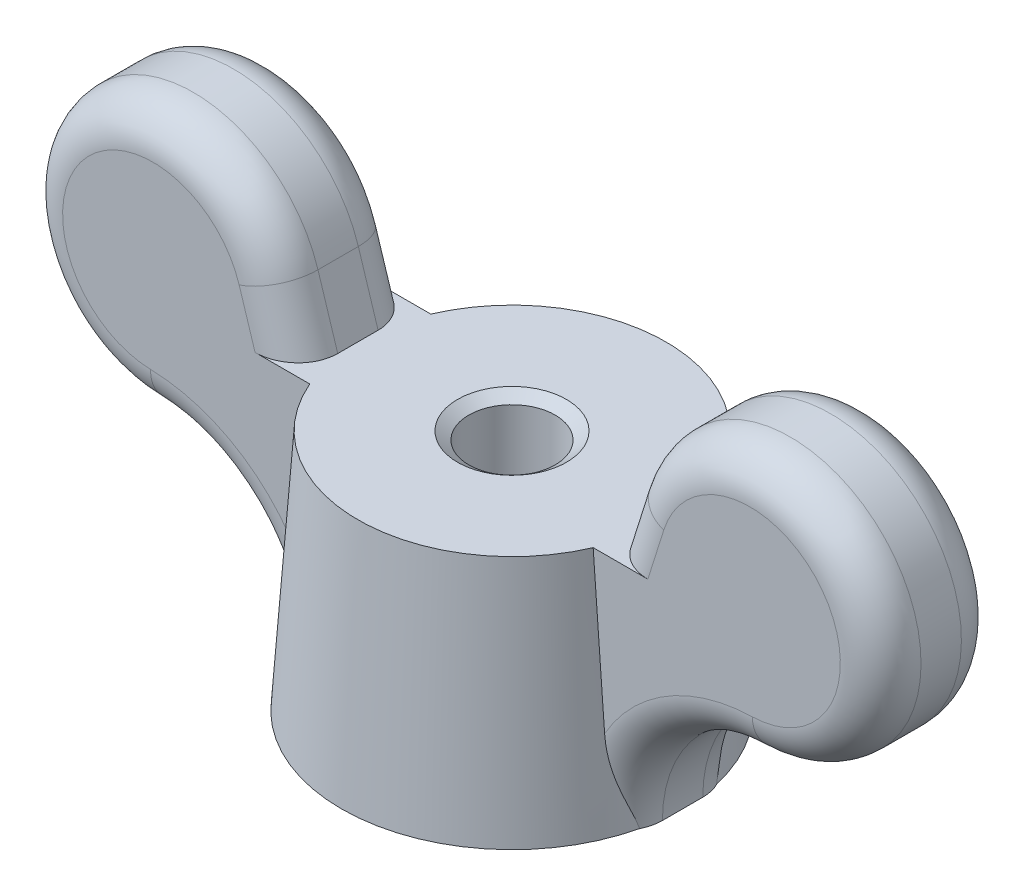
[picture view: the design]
ISO-10303-21;
HEADER;
FILE_DESCRIPTION(('STEP AP214'),'2;1');
FILE_NAME('part.step','',(''),(''),'','','');
FILE_SCHEMA(('AUTOMOTIVE_DESIGN { 1 0 10303 214 1 1 1 1 }'));
ENDSEC;
DATA;
#1=APPLICATION_CONTEXT('core data for automotive mechanical design processes');
#2=APPLICATION_PROTOCOL_DEFINITION('international standard','automotive_design',2000,#1);
#3=PRODUCT_CONTEXT('',#1,'mechanical');
#4=PRODUCT('Part','Part','',(#3));
#5=PRODUCT_RELATED_PRODUCT_CATEGORY('part','',(#4));
#6=PRODUCT_DEFINITION_FORMATION('','',#4);
#7=PRODUCT_DEFINITION_CONTEXT('part definition',#1,'design');
#8=PRODUCT_DEFINITION('design','',#6,#7);
#9=PRODUCT_DEFINITION_SHAPE('','',#8);
#10=(LENGTH_UNIT() NAMED_UNIT(*) SI_UNIT(.MILLI.,.METRE.));
#11=(NAMED_UNIT(*) PLANE_ANGLE_UNIT() SI_UNIT($,.RADIAN.));
#12=(NAMED_UNIT(*) SI_UNIT($,.STERADIAN.) SOLID_ANGLE_UNIT());
#13=UNCERTAINTY_MEASURE_WITH_UNIT(LENGTH_MEASURE(1.E-05),#10,'distance_accuracy_value','');
#14=(GEOMETRIC_REPRESENTATION_CONTEXT(3) GLOBAL_UNCERTAINTY_ASSIGNED_CONTEXT((#13)) GLOBAL_UNIT_ASSIGNED_CONTEXT((#10,
#11,#12)) REPRESENTATION_CONTEXT('',''));
#15=CARTESIAN_POINT('',(0.,0.,0.));
#16=DIRECTION('',(0.,0.,1.));
#17=DIRECTION('',(1.,0.,0.));
#18=AXIS2_PLACEMENT_3D('',#15,#16,#17);
#19=CARTESIAN_POINT('',(3.93700000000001,0.,1.397));
#20=DIRECTION('',(0.,1.,0.));
#21=DIRECTION('',(-1.,0.,0.));
#22=AXIS2_PLACEMENT_3D('',#19,#20,#21);
#23=PLANE('',#22);
#24=CARTESIAN_POINT('',(0.,0.,0.));
#25=DIRECTION('',(0.,-1.,0.));
#26=DIRECTION('',(0.,0.,-1.));
#27=AXIS2_PLACEMENT_3D('',#24,#25,#26);
#28=CIRCLE('',#27,3.937);
#29=CARTESIAN_POINT('',(-3.83538975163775,0.,-0.888681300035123));
#30=VERTEX_POINT('',#29);
#31=CARTESIAN_POINT('',(3.83538975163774,0.,-0.88868130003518));
#32=VERTEX_POINT('',#31);
#33=EDGE_CURVE('E212',#30,#32,#28,.T.);
#34=ORIENTED_EDGE('',*,*,#33,.T.);
#35=CARTESIAN_POINT('',(3.00566666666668,0.,-0.465666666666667));
#36=DIRECTION('',(0.,1.,0.));
#37=DIRECTION('',(-1.,0.,0.));
#38=AXIS2_PLACEMENT_3D('',#35,#36,#37);
#39=CIRCLE('',#38,0.931333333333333);
#40=CARTESIAN_POINT('',(3.93700000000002,0.,-0.465666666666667));
#41=VERTEX_POINT('',#40);
#42=EDGE_CURVE('E436',#32,#41,#39,.F.);
#43=ORIENTED_EDGE('',*,*,#42,.T.);
#44=DIRECTION('',(0.,0.,-1.));
#45=VECTOR('',#44,1.);
#46=CARTESIAN_POINT('',(3.93700000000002,0.,1.397));
#47=LINE('',#46,#45);
#48=CARTESIAN_POINT('',(3.93700000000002,0.,0.465666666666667));
#49=VERTEX_POINT('',#48);
#50=EDGE_CURVE('E475',#49,#41,#47,.T.);
#51=ORIENTED_EDGE('',*,*,#50,.F.);
#52=CARTESIAN_POINT('',(3.00566666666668,0.,0.465666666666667));
#53=DIRECTION('',(0.,1.,0.));
#54=DIRECTION('',(-1.,0.,0.));
#55=AXIS2_PLACEMENT_3D('',#52,#53,#54);
#56=CIRCLE('',#55,0.931333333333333);
#57=CARTESIAN_POINT('',(3.83538975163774,0.,0.88868130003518));
#58=VERTEX_POINT('',#57);
#59=EDGE_CURVE('E441',#49,#58,#56,.F.);
#60=ORIENTED_EDGE('',*,*,#59,.T.);
#61=CARTESIAN_POINT('',(-3.83538975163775,0.,0.888681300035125));
#62=VERTEX_POINT('',#61);
#63=EDGE_CURVE('E199',#58,#62,#28,.T.);
#64=ORIENTED_EDGE('',*,*,#63,.T.);
#65=CARTESIAN_POINT('',(-3.00566666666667,0.,0.465666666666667));
#66=DIRECTION('',(0.,1.,0.));
#67=DIRECTION('',(-1.,0.,0.));
#68=AXIS2_PLACEMENT_3D('',#65,#66,#67);
#69=CIRCLE('',#68,0.931333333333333);
#70=CARTESIAN_POINT('',(-3.937,0.,0.465666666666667));
#71=VERTEX_POINT('',#70);
#72=EDGE_CURVE('E444',#62,#71,#69,.F.);
#73=ORIENTED_EDGE('',*,*,#72,.T.);
#74=DIRECTION('',(0.,0.,-1.));
#75=VECTOR('',#74,1.);
#76=CARTESIAN_POINT('',(-3.937,0.,1.397));
#77=LINE('',#76,#75);
#78=CARTESIAN_POINT('',(-3.937,0.,-0.465666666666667));
#79=VERTEX_POINT('',#78);
#80=EDGE_CURVE('E470',#71,#79,#77,.T.);
#81=ORIENTED_EDGE('',*,*,#80,.T.);
#82=CARTESIAN_POINT('',(-3.00566666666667,0.,-0.465666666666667));
#83=DIRECTION('',(0.,1.,0.));
#84=DIRECTION('',(-1.,0.,0.));
#85=AXIS2_PLACEMENT_3D('',#82,#83,#84);
#86=CIRCLE('',#85,0.931333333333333);
#87=EDGE_CURVE('E438',#79,#30,#86,.F.);
#88=ORIENTED_EDGE('',*,*,#87,.T.);
#89=EDGE_LOOP('',(#34,#43,#51,#60,#64,#73,#81,#88));
#90=FACE_BOUND('',#89,.T.);
#91=CARTESIAN_POINT('',(0.,0.,0.));
#92=DIRECTION('',(0.,1.,0.));
#93=DIRECTION('',(-1.,0.,0.));
#94=AXIS2_PLACEMENT_3D('',#91,#92,#93);
#95=CIRCLE('',#94,1.25729999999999);
#96=CARTESIAN_POINT('',(-1.25729999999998,0.,0.));
#97=VERTEX_POINT('',#96);
#98=EDGE_CURVE('E500',#97,#97,#95,.T.);
#99=ORIENTED_EDGE('',*,*,#98,.T.);
#100=EDGE_LOOP('',(#99));
#101=FACE_BOUND('',#100,.T.);
#102=ADVANCED_FACE('F47',(#90,#101),#23,.F.);
#103=CARTESIAN_POINT('',(6.88920679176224,6.12720679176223,1.397));
#104=DIRECTION('',(0.,0.,-1.));
#105=DIRECTION('',(-1.,0.,0.));
#106=AXIS2_PLACEMENT_3D('',#103,#104,#105);
#107=PLANE('',#106);
#108=CARTESIAN_POINT('',(-6.88920679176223,6.12720679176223,1.397));
#109=DIRECTION('',(0.,0.,-1.));
#110=DIRECTION('',(-1.,0.,0.));
#111=AXIS2_PLACEMENT_3D('',#108,#109,#110);
#112=CIRCLE('',#111,2.08545987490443);
#113=CARTESIAN_POINT('',(-4.90026835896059,6.75431667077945,1.397));
#114=VERTEX_POINT('',#113);
#115=CARTESIAN_POINT('',(-6.9437490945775,4.04246027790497,1.397));
#116=VERTEX_POINT('',#115);
#117=EDGE_CURVE('E398',#114,#116,#112,.F.);
#118=ORIENTED_EDGE('',*,*,#117,.T.);
#119=CARTESIAN_POINT('',(-7.04951019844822,0.,1.397));
#120=DIRECTION('',(0.,0.,-1.));
#121=DIRECTION('',(-1.,0.,0.));
#122=AXIS2_PLACEMENT_3D('',#119,#120,#121);
#123=CIRCLE('',#122,4.04384353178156);
#124=CARTESIAN_POINT('',(-3.53461000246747,1.9995367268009,1.397));
#125=VERTEX_POINT('',#124);
#126=EDGE_CURVE('E409',#116,#125,#123,.T.);
#127=ORIENTED_EDGE('',*,*,#126,.T.);
#128=CARTESIAN_POINT('',(-2.53867458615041,15.2435415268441,1.397));
#129=CARTESIAN_POINT('',(-2.60883110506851,14.3418946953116,1.397));
#130=CARTESIAN_POINT('',(-2.67834194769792,13.4401979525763,1.397));
#131=CARTESIAN_POINT('',(-2.81629610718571,11.6367239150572,1.397));
#132=CARTESIAN_POINT('',(-2.88473942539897,10.7349466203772,1.397));
#133=CARTESIAN_POINT('',(-3.0752390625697,8.20936047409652,1.397));
#134=CARTESIAN_POINT('',(-3.19634976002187,6.58548035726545,1.397));
#135=CARTESIAN_POINT('',(-3.43663846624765,3.33757667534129,1.397));
#136=CARTESIAN_POINT('',(-3.55581647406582,1.71355311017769,1.397));
#137=CARTESIAN_POINT('',(-3.79275127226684,-1.53460548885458,1.397));
#138=CARTESIAN_POINT('',(-3.91050805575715,-3.15874052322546,1.397));
#139=CARTESIAN_POINT('',(-4.14491971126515,-6.40708829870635,1.397));
#140=CARTESIAN_POINT('',(-4.26157458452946,-8.03130103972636,1.397));
#141=CARTESIAN_POINT('',(-4.37783858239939,-9.65554152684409,1.397));
#142=B_SPLINE_CURVE_WITH_KNOTS('',3,(#128,#129,#130,#131,#132,#133,#134,#135,#136,#137,#138,
#139,#140,#141),.UNSPECIFIED.,.F.,.F.,(4,2,2,2,2,2,4),(0.,2.71311566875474,5.42622789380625,
10.3113965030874,15.1965675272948,20.0817622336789,24.9669514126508),.UNSPECIFIED.);
#143=CARTESIAN_POINT('',(-3.27009587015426,5.588,1.397));
#144=VERTEX_POINT('',#143);
#145=EDGE_CURVE('E198',#144,#125,#142,.T.);
#146=ORIENTED_EDGE('',*,*,#145,.F.);
#147=DIRECTION('',(-1.,0.,0.));
#148=VECTOR('',#147,1.);
#149=CARTESIAN_POINT('',(-3.55599999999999,5.588,1.397));
#150=LINE('',#149,#148);
#151=CARTESIAN_POINT('',(-4.53253012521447,5.588,1.397));
#152=VERTEX_POINT('',#151);
#153=EDGE_CURVE('E208',#144,#152,#150,.T.);
#154=ORIENTED_EDGE('',*,*,#153,.T.);
#155=DIRECTION('',(-0.300705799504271,0.953716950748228,0.));
#156=VECTOR('',#155,1.);
#157=CARTESIAN_POINT('',(-3.65436939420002,2.80282998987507,1.397));
#158=LINE('',#157,#156);
#159=EDGE_CURVE('E401',#152,#114,#158,.T.);
#160=ORIENTED_EDGE('',*,*,#159,.T.);
#161=EDGE_LOOP('',(#118,#127,#146,#154,#160));
#162=FACE_BOUND('',#161,.T.);
#163=ADVANCED_FACE('F232',(#162),#107,.F.);
#164=CARTESIAN_POINT('',(4.37783858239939,-9.65554152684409,1.397));
#165=CARTESIAN_POINT('',(4.27544426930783,-8.2249837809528,1.397));
#166=CARTESIAN_POINT('',(4.17273962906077,-6.79444812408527,1.397));
#167=CARTESIAN_POINT('',(3.96650348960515,-3.93343820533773,1.397));
#168=CARTESIAN_POINT('',(3.86297199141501,-2.50296394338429,1.397));
#169=CARTESIAN_POINT('',(3.66000814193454,0.287349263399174,1.397));
#170=CARTESIAN_POINT('',(3.56062550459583,1.64719182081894,1.397));
#171=CARTESIAN_POINT('',(3.36066061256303,4.36678847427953,1.397));
#172=CARTESIAN_POINT('',(3.26007835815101,5.72654257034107,1.397));
#173=CARTESIAN_POINT('',(3.05734265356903,8.44593710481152,1.397));
#174=CARTESIAN_POINT('',(2.95518919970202,9.80557754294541,1.397));
#175=CARTESIAN_POINT('',(2.80035690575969,11.8449172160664,1.397));
#176=CARTESIAN_POINT('',(2.74847909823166,12.524677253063,1.397));
#177=CARTESIAN_POINT('',(2.64408340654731,13.8841483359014,1.397));
#178=CARTESIAN_POINT('',(2.59156552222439,14.5638593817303,1.397));
#179=CARTESIAN_POINT('',(2.53867458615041,15.2435415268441,1.397));
#180=B_SPLINE_CURVE_WITH_KNOTS('',3,(#164,#165,#166,#167,#168,#169,#170,#171,#172,#173,#174,
#175,#176,#177,#178,#179),.UNSPECIFIED.,.F.,.F.,(4,2,2,2,2,2,2,4),(0.,4.30265288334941,
8.60530046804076,12.6957081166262,16.786114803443,20.8765311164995,22.9217411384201,
24.9669516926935),.UNSPECIFIED.);
#181=CARTESIAN_POINT('',(3.53461000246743,1.99953672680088,1.397));
#182=VERTEX_POINT('',#181);
#183=CARTESIAN_POINT('',(3.27009587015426,5.588,1.397));
#184=VERTEX_POINT('',#183);
#185=EDGE_CURVE('E187',#182,#184,#180,.T.);
#186=ORIENTED_EDGE('',*,*,#185,.F.);
#187=CARTESIAN_POINT('',(7.04951019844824,0.,1.397));
#188=DIRECTION('',(0.,0.,-1.));
#189=DIRECTION('',(-1.,0.,0.));
#190=AXIS2_PLACEMENT_3D('',#187,#188,#189);
#191=CIRCLE('',#190,4.04384353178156);
#192=CARTESIAN_POINT('',(6.94374909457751,4.04246027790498,1.397));
#193=VERTEX_POINT('',#192);
#194=EDGE_CURVE('E414',#182,#193,#191,.T.);
#195=ORIENTED_EDGE('',*,*,#194,.T.);
#196=CARTESIAN_POINT('',(6.88920679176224,6.12720679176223,1.397));
#197=DIRECTION('',(0.,0.,-1.));
#198=DIRECTION('',(-1.,0.,0.));
#199=AXIS2_PLACEMENT_3D('',#196,#197,#198);
#200=CIRCLE('',#199,2.08545987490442);
#201=CARTESIAN_POINT('',(4.90026835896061,6.75431667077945,1.397));
#202=VERTEX_POINT('',#201);
#203=EDGE_CURVE('E416',#193,#202,#200,.F.);
#204=ORIENTED_EDGE('',*,*,#203,.T.);
#205=DIRECTION('',(-0.300705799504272,-0.953716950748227,0.));
#206=VECTOR('',#205,1.);
#207=CARTESIAN_POINT('',(4.90026835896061,6.75431667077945,1.397));
#208=LINE('',#207,#206);
#209=CARTESIAN_POINT('',(4.53253012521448,5.588,1.397));
#210=VERTEX_POINT('',#209);
#211=EDGE_CURVE('E205',#202,#210,#208,.T.);
#212=ORIENTED_EDGE('',*,*,#211,.T.);
#213=EDGE_CURVE('E202',#210,#184,#150,.T.);
#214=ORIENTED_EDGE('',*,*,#213,.T.);
#215=EDGE_LOOP('',(#186,#195,#204,#212,#214));
#216=FACE_BOUND('',#215,.T.);
#217=ADVANCED_FACE('F203',(#216),#107,.F.);
#218=CARTESIAN_POINT('',(6.88920679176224,6.12720679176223,-1.397));
#219=DIRECTION('',(0.,0.,-1.));
#220=DIRECTION('',(-1.,0.,0.));
#221=AXIS2_PLACEMENT_3D('',#218,#219,#220);
#222=PLANE('',#221);
#223=CARTESIAN_POINT('',(-2.53867458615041,15.2435415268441,-1.397));
#224=CARTESIAN_POINT('',(-2.60883110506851,14.3418946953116,-1.397));
#225=CARTESIAN_POINT('',(-2.67834194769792,13.4401979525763,-1.397));
#226=CARTESIAN_POINT('',(-2.81629610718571,11.6367239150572,-1.397));
#227=CARTESIAN_POINT('',(-2.88473942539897,10.7349466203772,-1.397));
#228=CARTESIAN_POINT('',(-3.0752390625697,8.20936047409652,-1.397));
#229=CARTESIAN_POINT('',(-3.19634976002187,6.58548035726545,-1.397));
#230=CARTESIAN_POINT('',(-3.43663846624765,3.33757667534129,-1.397));
#231=CARTESIAN_POINT('',(-3.55581647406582,1.71355311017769,-1.397));
#232=CARTESIAN_POINT('',(-3.79275127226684,-1.53460548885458,-1.397));
#233=CARTESIAN_POINT('',(-3.91050805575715,-3.15874052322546,-1.397));
#234=CARTESIAN_POINT('',(-4.14491971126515,-6.40708829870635,-1.397));
#235=CARTESIAN_POINT('',(-4.26157458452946,-8.03130103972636,-1.397));
#236=CARTESIAN_POINT('',(-4.37783858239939,-9.65554152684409,-1.397));
#237=B_SPLINE_CURVE_WITH_KNOTS('',3,(#223,#224,#225,#226,#227,#228,#229,#230,#231,#232,#233,
#234,#235,#236),.UNSPECIFIED.,.F.,.F.,(4,2,2,2,2,2,4),(0.,2.71311566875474,5.42622789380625,
10.3113965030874,15.1965675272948,20.0817622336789,24.9669514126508),.UNSPECIFIED.);
#238=CARTESIAN_POINT('',(-3.27009587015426,5.588,-1.397));
#239=VERTEX_POINT('',#238);
#240=CARTESIAN_POINT('',(-3.53461000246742,1.9995367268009,-1.397));
#241=VERTEX_POINT('',#240);
#242=EDGE_CURVE('E255',#239,#241,#237,.T.);
#243=ORIENTED_EDGE('',*,*,#242,.T.);
#244=CARTESIAN_POINT('',(-7.04951019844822,0.,-1.397));
#245=DIRECTION('',(0.,0.,-1.));
#246=DIRECTION('',(-1.,0.,0.));
#247=AXIS2_PLACEMENT_3D('',#244,#245,#246);
#248=CIRCLE('',#247,4.04384353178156);
#249=CARTESIAN_POINT('',(-6.9437490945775,4.04246027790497,-1.397));
#250=VERTEX_POINT('',#249);
#251=EDGE_CURVE('E421',#241,#250,#248,.F.);
#252=ORIENTED_EDGE('',*,*,#251,.T.);
#253=CARTESIAN_POINT('',(-6.88920679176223,6.12720679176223,-1.397));
#254=DIRECTION('',(0.,0.,-1.));
#255=DIRECTION('',(-1.,0.,0.));
#256=AXIS2_PLACEMENT_3D('',#253,#254,#255);
#257=CIRCLE('',#256,2.08545987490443);
#258=CARTESIAN_POINT('',(-4.90026835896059,6.75431667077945,-1.397));
#259=VERTEX_POINT('',#258);
#260=EDGE_CURVE('E372',#250,#259,#257,.T.);
#261=ORIENTED_EDGE('',*,*,#260,.T.);
#262=DIRECTION('',(-0.300705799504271,0.953716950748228,0.));
#263=VECTOR('',#262,1.);
#264=CARTESIAN_POINT('',(-4.44422838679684,5.30794266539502,-1.397));
#265=LINE('',#264,#263);
#266=CARTESIAN_POINT('',(-4.53253012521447,5.588,-1.397));
#267=VERTEX_POINT('',#266);
#268=EDGE_CURVE('E424',#259,#267,#265,.F.);
#269=ORIENTED_EDGE('',*,*,#268,.T.);
#270=DIRECTION('',(-1.,0.,0.));
#271=VECTOR('',#270,1.);
#272=CARTESIAN_POINT('',(-3.55599999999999,5.588,-1.397));
#273=LINE('',#272,#271);
#274=EDGE_CURVE('E489',#239,#267,#273,.T.);
#275=ORIENTED_EDGE('',*,*,#274,.F.);
#276=EDGE_LOOP('',(#243,#252,#261,#269,#275));
#277=FACE_BOUND('',#276,.T.);
#278=ADVANCED_FACE('F526',(#277),#222,.T.);
#279=CARTESIAN_POINT('',(6.88920679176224,6.12720679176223,-1.397));
#280=DIRECTION('',(0.,0.,-1.));
#281=DIRECTION('',(-1.,0.,0.));
#282=AXIS2_PLACEMENT_3D('',#279,#280,#281);
#283=CIRCLE('',#282,2.08545987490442);
#284=CARTESIAN_POINT('',(4.90026835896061,6.75431667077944,-1.397));
#285=VERTEX_POINT('',#284);
#286=CARTESIAN_POINT('',(6.94374909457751,4.04246027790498,-1.397));
#287=VERTEX_POINT('',#286);
#288=EDGE_CURVE('E448',#285,#287,#283,.T.);
#289=ORIENTED_EDGE('',*,*,#288,.T.);
#290=CARTESIAN_POINT('',(7.04951019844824,0.,-1.397));
#291=DIRECTION('',(0.,0.,-1.));
#292=DIRECTION('',(-1.,0.,0.));
#293=AXIS2_PLACEMENT_3D('',#290,#291,#292);
#294=CIRCLE('',#293,4.04384353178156);
#295=CARTESIAN_POINT('',(3.53461000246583,1.99953672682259,-1.397));
#296=VERTEX_POINT('',#295);
#297=EDGE_CURVE('E446',#287,#296,#294,.F.);
#298=ORIENTED_EDGE('',*,*,#297,.T.);
#299=CARTESIAN_POINT('',(4.37783858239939,-9.65554152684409,-1.397));
#300=CARTESIAN_POINT('',(4.27544426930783,-8.2249837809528,-1.397));
#301=CARTESIAN_POINT('',(4.17273962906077,-6.79444812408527,-1.397));
#302=CARTESIAN_POINT('',(3.96650348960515,-3.93343820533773,-1.397));
#303=CARTESIAN_POINT('',(3.86297199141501,-2.50296394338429,-1.397));
#304=CARTESIAN_POINT('',(3.66000814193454,0.287349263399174,-1.397));
#305=CARTESIAN_POINT('',(3.56062550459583,1.64719182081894,-1.397));
#306=CARTESIAN_POINT('',(3.36066061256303,4.36678847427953,-1.397));
#307=CARTESIAN_POINT('',(3.26007835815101,5.72654257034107,-1.397));
#308=CARTESIAN_POINT('',(3.05734265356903,8.44593710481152,-1.397));
#309=CARTESIAN_POINT('',(2.95518919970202,9.80557754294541,-1.397));
#310=CARTESIAN_POINT('',(2.80035690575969,11.8449172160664,-1.397));
#311=CARTESIAN_POINT('',(2.74847909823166,12.524677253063,-1.397));
#312=CARTESIAN_POINT('',(2.64408340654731,13.8841483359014,-1.397));
#313=CARTESIAN_POINT('',(2.59156552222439,14.5638593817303,-1.397));
#314=CARTESIAN_POINT('',(2.53867458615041,15.2435415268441,-1.397));
#315=B_SPLINE_CURVE_WITH_KNOTS('',3,(#299,#300,#301,#302,#303,#304,#305,#306,#307,#308,#309,
#310,#311,#312,#313,#314),.UNSPECIFIED.,.F.,.F.,(4,2,2,2,2,2,2,4),(0.,4.30265288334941,
8.60530046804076,12.6957081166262,16.786114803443,20.8765311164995,22.9217411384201,
24.9669516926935),.UNSPECIFIED.);
#316=CARTESIAN_POINT('',(3.27009587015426,5.588,-1.397));
#317=VERTEX_POINT('',#316);
#318=EDGE_CURVE('E245',#296,#317,#315,.T.);
#319=ORIENTED_EDGE('',*,*,#318,.T.);
#320=CARTESIAN_POINT('',(4.53253012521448,5.588,-1.397));
#321=VERTEX_POINT('',#320);
#322=EDGE_CURVE('E487',#321,#317,#273,.T.);
#323=ORIENTED_EDGE('',*,*,#322,.F.);
#324=DIRECTION('',(-0.300705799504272,-0.953716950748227,0.));
#325=VECTOR('',#324,1.);
#326=CARTESIAN_POINT('',(4.90026835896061,6.75431667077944,-1.397));
#327=LINE('',#326,#325);
#328=EDGE_CURVE('E450',#321,#285,#327,.F.);
#329=ORIENTED_EDGE('',*,*,#328,.T.);
#330=EDGE_LOOP('',(#289,#298,#319,#323,#329));
#331=FACE_BOUND('',#330,.T.);
#332=ADVANCED_FACE('F343',(#331),#222,.T.);
#333=CARTESIAN_POINT('',(-4.01203997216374,7.03437400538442,1.397));
#334=DIRECTION('',(-0.953716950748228,-0.300705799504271,0.));
#335=DIRECTION('',(0.300705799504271,-0.953716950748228,0.));
#336=AXIS2_PLACEMENT_3D('',#333,#334,#335);
#337=PLANE('',#336);
#338=DIRECTION('',(0.,0.,-1.));
#339=VECTOR('',#338,1.);
#340=CARTESIAN_POINT('',(-3.55599999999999,5.588,1.397));
#341=LINE('',#340,#339);
#342=CARTESIAN_POINT('',(-3.55599999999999,5.588,0.465666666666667));
#343=VERTEX_POINT('',#342);
#344=CARTESIAN_POINT('',(-3.55599999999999,5.588,-0.465666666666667));
#345=VERTEX_POINT('',#344);
#346=EDGE_CURVE('E207',#343,#345,#341,.T.);
#347=ORIENTED_EDGE('',*,*,#346,.T.);
#348=DIRECTION('',(-0.300705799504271,0.953716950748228,0.));
#349=VECTOR('',#348,1.);
#350=CARTESIAN_POINT('',(-4.01203997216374,7.03437400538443,-0.465666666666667));
#351=LINE('',#350,#349);
#352=CARTESIAN_POINT('',(-4.01203997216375,7.03437400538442,-0.465666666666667));
#353=VERTEX_POINT('',#352);
#354=EDGE_CURVE('E402',#345,#353,#351,.T.);
#355=ORIENTED_EDGE('',*,*,#354,.T.);
#356=DIRECTION('',(0.,0.,-1.));
#357=VECTOR('',#356,1.);
#358=CARTESIAN_POINT('',(-4.01203997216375,7.03437400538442,1.397));
#359=LINE('',#358,#357);
#360=CARTESIAN_POINT('',(-4.01203997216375,7.03437400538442,0.465666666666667));
#361=VERTEX_POINT('',#360);
#362=EDGE_CURVE('E464',#361,#353,#359,.T.);
#363=ORIENTED_EDGE('',*,*,#362,.F.);
#364=DIRECTION('',(-0.300705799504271,0.953716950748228,0.));
#365=VECTOR('',#364,1.);
#366=CARTESIAN_POINT('',(-4.01203997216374,7.03437400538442,0.465666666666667));
#367=LINE('',#366,#365);
#368=EDGE_CURVE('E71',#361,#343,#367,.F.);
#369=ORIENTED_EDGE('',*,*,#368,.T.);
#370=EDGE_LOOP('',(#347,#355,#363,#369));
#371=FACE_BOUND('',#370,.T.);
#372=ADVANCED_FACE('F340',(#371),#337,.F.);
#373=CARTESIAN_POINT('',(-6.88920679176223,6.12720679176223,1.397));
#374=DIRECTION('',(0.,0.,-1.));
#375=DIRECTION('',(-1.,0.,0.));
#376=AXIS2_PLACEMENT_3D('',#373,#374,#375);
#377=CYLINDRICAL_SURFACE('',#376,3.01679320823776);
#378=ORIENTED_EDGE('',*,*,#362,.T.);
#379=CARTESIAN_POINT('',(-6.88920679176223,6.12720679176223,-0.465666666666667));
#380=DIRECTION('',(0.,0.,-1.));
#381=DIRECTION('',(-1.,0.,0.));
#382=AXIS2_PLACEMENT_3D('',#379,#380,#381);
#383=CIRCLE('',#382,3.01679320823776);
#384=CARTESIAN_POINT('',(-6.96810682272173,3.11144552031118,-0.465666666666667));
#385=VERTEX_POINT('',#384);
#386=EDGE_CURVE('E374',#353,#385,#383,.F.);
#387=ORIENTED_EDGE('',*,*,#386,.T.);
#388=DIRECTION('',(0.,0.,-1.));
#389=VECTOR('',#388,1.);
#390=CARTESIAN_POINT('',(-6.96810682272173,3.11144552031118,1.397));
#391=LINE('',#390,#389);
#392=CARTESIAN_POINT('',(-6.96810682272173,3.11144552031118,0.465666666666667));
#393=VERTEX_POINT('',#392);
#394=EDGE_CURVE('E468',#393,#385,#391,.T.);
#395=ORIENTED_EDGE('',*,*,#394,.F.);
#396=CARTESIAN_POINT('',(-6.88920679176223,6.12720679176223,0.465666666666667));
#397=DIRECTION('',(0.,0.,-1.));
#398=DIRECTION('',(-1.,0.,0.));
#399=AXIS2_PLACEMENT_3D('',#396,#397,#398);
#400=CIRCLE('',#399,3.01679320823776);
#401=EDGE_CURVE('E397',#393,#361,#400,.T.);
#402=ORIENTED_EDGE('',*,*,#401,.T.);
#403=EDGE_LOOP('',(#378,#387,#395,#402));
#404=FACE_BOUND('',#403,.T.);
#405=ADVANCED_FACE('F336',(#404),#377,.T.);
#406=CARTESIAN_POINT('',(-7.04951019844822,0.,1.397));
#407=DIRECTION('',(0.,0.,-1.));
#408=DIRECTION('',(-1.,0.,0.));
#409=AXIS2_PLACEMENT_3D('',#406,#407,#408);
#410=CYLINDRICAL_SURFACE('',#409,3.11251019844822);
#411=ORIENTED_EDGE('',*,*,#394,.T.);
#412=CARTESIAN_POINT('',(-7.04951019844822,0.,-0.465666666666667));
#413=DIRECTION('',(0.,0.,-1.));
#414=DIRECTION('',(-1.,0.,0.));
#415=AXIS2_PLACEMENT_3D('',#412,#413,#414);
#416=CIRCLE('',#415,3.11251019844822);
#417=EDGE_CURVE('E427',#385,#79,#416,.T.);
#418=ORIENTED_EDGE('',*,*,#417,.T.);
#419=ORIENTED_EDGE('',*,*,#80,.F.);
#420=CARTESIAN_POINT('',(-7.04951019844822,0.,0.465666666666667));
#421=DIRECTION('',(0.,0.,-1.));
#422=DIRECTION('',(-1.,0.,0.));
#423=AXIS2_PLACEMENT_3D('',#420,#421,#422);
#424=CIRCLE('',#423,3.11251019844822);
#425=EDGE_CURVE('E430',#71,#393,#424,.F.);
#426=ORIENTED_EDGE('',*,*,#425,.T.);
#427=EDGE_LOOP('',(#411,#418,#419,#426));
#428=FACE_BOUND('',#427,.T.);
#429=ADVANCED_FACE('F333',(#428),#410,.F.);
#430=CARTESIAN_POINT('',(7.04951019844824,0.,1.397));
#431=DIRECTION('',(0.,0.,-1.));
#432=DIRECTION('',(-1.,0.,0.));
#433=AXIS2_PLACEMENT_3D('',#430,#431,#432);
#434=CYLINDRICAL_SURFACE('',#433,3.11251019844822);
#435=ORIENTED_EDGE('',*,*,#50,.T.);
#436=CARTESIAN_POINT('',(7.04951019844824,0.,-0.465666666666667));
#437=DIRECTION('',(0.,0.,-1.));
#438=DIRECTION('',(-1.,0.,0.));
#439=AXIS2_PLACEMENT_3D('',#436,#437,#438);
#440=CIRCLE('',#439,3.11251019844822);
#441=CARTESIAN_POINT('',(6.96810682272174,3.11144552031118,-0.465666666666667));
#442=VERTEX_POINT('',#441);
#443=EDGE_CURVE('E452',#41,#442,#440,.T.);
#444=ORIENTED_EDGE('',*,*,#443,.T.);
#445=DIRECTION('',(0.,0.,-1.));
#446=VECTOR('',#445,1.);
#447=CARTESIAN_POINT('',(6.96810682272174,3.11144552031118,1.397));
#448=LINE('',#447,#446);
#449=CARTESIAN_POINT('',(6.96810682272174,3.11144552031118,0.465666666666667));
#450=VERTEX_POINT('',#449);
#451=EDGE_CURVE('E477',#450,#442,#448,.T.);
#452=ORIENTED_EDGE('',*,*,#451,.F.);
#453=CARTESIAN_POINT('',(7.04951019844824,0.,0.465666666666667));
#454=DIRECTION('',(0.,0.,-1.));
#455=DIRECTION('',(-1.,0.,0.));
#456=AXIS2_PLACEMENT_3D('',#453,#454,#455);
#457=CIRCLE('',#456,3.11251019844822);
#458=EDGE_CURVE('E454',#450,#49,#457,.F.);
#459=ORIENTED_EDGE('',*,*,#458,.T.);
#460=EDGE_LOOP('',(#435,#444,#452,#459));
#461=FACE_BOUND('',#460,.T.);
#462=ADVANCED_FACE('F331',(#461),#434,.F.);
#463=CARTESIAN_POINT('',(6.88920679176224,6.12720679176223,1.397));
#464=DIRECTION('',(0.,0.,-1.));
#465=DIRECTION('',(-1.,0.,0.));
#466=AXIS2_PLACEMENT_3D('',#463,#464,#465);
#467=CYLINDRICAL_SURFACE('',#466,3.01679320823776);
#468=ORIENTED_EDGE('',*,*,#451,.T.);
#469=CARTESIAN_POINT('',(6.88920679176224,6.12720679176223,-0.465666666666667));
#470=DIRECTION('',(0.,0.,-1.));
#471=DIRECTION('',(-1.,0.,0.));
#472=AXIS2_PLACEMENT_3D('',#469,#470,#471);
#473=CIRCLE('',#472,3.01679320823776);
#474=CARTESIAN_POINT('',(4.01203997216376,7.03437400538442,-0.465666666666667));
#475=VERTEX_POINT('',#474);
#476=EDGE_CURVE('E432',#442,#475,#473,.F.);
#477=ORIENTED_EDGE('',*,*,#476,.T.);
#478=DIRECTION('',(0.,0.,-1.));
#479=VECTOR('',#478,1.);
#480=CARTESIAN_POINT('',(4.01203997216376,7.03437400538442,1.397));
#481=LINE('',#480,#479);
#482=CARTESIAN_POINT('',(4.01203997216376,7.03437400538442,0.465666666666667));
#483=VERTEX_POINT('',#482);
#484=EDGE_CURVE('E480',#483,#475,#481,.T.);
#485=ORIENTED_EDGE('',*,*,#484,.F.);
#486=CARTESIAN_POINT('',(6.88920679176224,6.12720679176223,0.465666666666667));
#487=DIRECTION('',(0.,0.,-1.));
#488=DIRECTION('',(-1.,0.,0.));
#489=AXIS2_PLACEMENT_3D('',#486,#487,#488);
#490=CIRCLE('',#489,3.01679320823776);
#491=EDGE_CURVE('E434',#483,#450,#490,.T.);
#492=ORIENTED_EDGE('',*,*,#491,.T.);
#493=EDGE_LOOP('',(#468,#477,#485,#492));
#494=FACE_BOUND('',#493,.T.);
#495=ADVANCED_FACE('F523',(#494),#467,.T.);
#496=CARTESIAN_POINT('',(3.55600000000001,5.588,1.397));
#497=DIRECTION('',(0.953716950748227,-0.300705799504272,0.));
#498=DIRECTION('',(0.300705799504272,0.953716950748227,0.));
#499=AXIS2_PLACEMENT_3D('',#496,#497,#498);
#500=PLANE('',#499);
#501=ORIENTED_EDGE('',*,*,#484,.T.);
#502=DIRECTION('',(-0.300705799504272,-0.953716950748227,0.));
#503=VECTOR('',#502,1.);
#504=CARTESIAN_POINT('',(3.55600000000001,5.588,-0.465666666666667));
#505=LINE('',#504,#503);
#506=CARTESIAN_POINT('',(3.55600000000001,5.588,-0.465666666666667));
#507=VERTEX_POINT('',#506);
#508=EDGE_CURVE('E403',#475,#507,#505,.T.);
#509=ORIENTED_EDGE('',*,*,#508,.T.);
#510=DIRECTION('',(0.,0.,-1.));
#511=VECTOR('',#510,1.);
#512=CARTESIAN_POINT('',(3.55600000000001,5.588,1.397));
#513=LINE('',#512,#511);
#514=CARTESIAN_POINT('',(3.55600000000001,5.588,0.465666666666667));
#515=VERTEX_POINT('',#514);
#516=EDGE_CURVE('E483',#515,#507,#513,.T.);
#517=ORIENTED_EDGE('',*,*,#516,.F.);
#518=DIRECTION('',(-0.300705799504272,-0.953716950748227,0.));
#519=VECTOR('',#518,1.);
#520=CARTESIAN_POINT('',(3.55600000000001,5.588,0.465666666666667));
#521=LINE('',#520,#519);
#522=EDGE_CURVE('E405',#515,#483,#521,.F.);
#523=ORIENTED_EDGE('',*,*,#522,.T.);
#524=EDGE_LOOP('',(#501,#509,#517,#523));
#525=FACE_BOUND('',#524,.T.);
#526=ADVANCED_FACE('F518',(#525),#500,.F.);
#527=CARTESIAN_POINT('',(-3.55599999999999,5.588,1.397));
#528=DIRECTION('',(0.,-1.,0.));
#529=DIRECTION('',(1.,0.,0.));
#530=AXIS2_PLACEMENT_3D('',#527,#528,#529);
#531=PLANE('',#530);
#532=CARTESIAN_POINT('',(0.,5.588,0.));
#533=DIRECTION('',(0.,1.,0.));
#534=DIRECTION('',(-1.,0.,0.));
#535=AXIS2_PLACEMENT_3D('',#532,#533,#534);
#536=CIRCLE('',#535,1.25729999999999);
#537=CARTESIAN_POINT('',(-1.25729999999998,5.588,0.));
#538=VERTEX_POINT('',#537);
#539=EDGE_CURVE('E507',#538,#538,#536,.T.);
#540=ORIENTED_EDGE('',*,*,#539,.F.);
#541=EDGE_LOOP('',(#540));
#542=FACE_BOUND('',#541,.T.);
#543=ORIENTED_EDGE('',*,*,#213,.F.);
#544=CARTESIAN_POINT('',(4.53253012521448,5.588,0.465666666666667));
#545=DIRECTION('',(0.,-1.,0.));
#546=DIRECTION('',(-1.,0.,0.));
#547=AXIS2_PLACEMENT_3D('',#544,#545,#546);
#548=ELLIPSE('',#547,0.976530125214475,0.931333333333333);
#549=EDGE_CURVE('E56',#210,#515,#548,.T.);
#550=ORIENTED_EDGE('',*,*,#549,.T.);
#551=ORIENTED_EDGE('',*,*,#516,.T.);
#552=CARTESIAN_POINT('',(4.53253012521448,5.588,-0.465666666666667));
#553=DIRECTION('',(0.,-1.,0.));
#554=DIRECTION('',(1.,0.,0.));
#555=AXIS2_PLACEMENT_3D('',#552,#553,#554);
#556=ELLIPSE('',#555,0.976530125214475,0.931333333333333);
#557=EDGE_CURVE('E494',#507,#321,#556,.T.);
#558=ORIENTED_EDGE('',*,*,#557,.T.);
#559=ORIENTED_EDGE('',*,*,#322,.T.);
#560=CARTESIAN_POINT('',(0.,5.588,0.));
#561=DIRECTION('',(0.,-1.,0.));
#562=DIRECTION('',(0.,0.,-1.));
#563=AXIS2_PLACEMENT_3D('',#560,#561,#562);
#564=CIRCLE('',#563,3.55599999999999);
#565=EDGE_CURVE('E213',#239,#317,#564,.T.);
#566=ORIENTED_EDGE('',*,*,#565,.F.);
#567=ORIENTED_EDGE('',*,*,#274,.T.);
#568=CARTESIAN_POINT('',(-4.53253012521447,5.588,-0.465666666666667));
#569=DIRECTION('',(0.,-1.,0.));
#570=DIRECTION('',(1.,0.,0.));
#571=AXIS2_PLACEMENT_3D('',#568,#569,#570);
#572=ELLIPSE('',#571,0.976530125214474,0.931333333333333);
#573=EDGE_CURVE('E64',#267,#345,#572,.T.);
#574=ORIENTED_EDGE('',*,*,#573,.T.);
#575=ORIENTED_EDGE('',*,*,#346,.F.);
#576=CARTESIAN_POINT('',(-4.53253012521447,5.588,0.465666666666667));
#577=DIRECTION('',(0.,-1.,0.));
#578=DIRECTION('',(-1.,0.,0.));
#579=AXIS2_PLACEMENT_3D('',#576,#577,#578);
#580=ELLIPSE('',#579,0.976530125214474,0.931333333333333);
#581=EDGE_CURVE('E11',#343,#152,#580,.T.);
#582=ORIENTED_EDGE('',*,*,#581,.T.);
#583=ORIENTED_EDGE('',*,*,#153,.F.);
#584=EDGE_CURVE('E192',#184,#144,#564,.T.);
#585=ORIENTED_EDGE('',*,*,#584,.F.);
#586=EDGE_LOOP('',(#543,#550,#551,#558,#559,#566,#567,#574,#575,#582,#583,#585));
#587=FACE_BOUND('',#586,.T.);
#588=ADVANCED_FACE('F211',(#542,#587),#531,.F.);
#589=CARTESIAN_POINT('',(0.,5.588,0.));
#590=DIRECTION('',(0.,-1.,0.));
#591=DIRECTION('',(0.,0.,-1.));
#592=AXIS2_PLACEMENT_3D('',#589,#590,#591);
#593=CONICAL_SURFACE('',#592,3.55599999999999,0.0680764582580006);
#594=ORIENTED_EDGE('',*,*,#242,.F.);
#595=ORIENTED_EDGE('',*,*,#565,.T.);
#596=ORIENTED_EDGE('',*,*,#318,.F.);
#597=CARTESIAN_POINT('',(3.53461000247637,1.9995367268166,-1.397));
#598=CARTESIAN_POINT('',(3.5403856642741,1.92056024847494,-1.3970008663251));
#599=CARTESIAN_POINT('',(3.54741439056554,1.84172264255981,-1.39387313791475));
#600=CARTESIAN_POINT('',(3.5636036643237,1.68474687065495,-1.38185084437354));
#601=CARTESIAN_POINT('',(3.57276300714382,1.60660833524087,-1.3729595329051));
#602=CARTESIAN_POINT('',(3.59275731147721,1.45205231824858,-1.3500017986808));
#603=CARTESIAN_POINT('',(3.60357665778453,1.37562571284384,-1.33598207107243));
#604=CARTESIAN_POINT('',(3.62651629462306,1.22400343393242,-1.30328976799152));
#605=CARTESIAN_POINT('',(3.63863629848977,1.1488074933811,-1.28461821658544));
#606=CARTESIAN_POINT('',(3.66646560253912,0.983393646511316,-1.23869667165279));
#607=CARTESIAN_POINT('',(3.68238034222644,0.8934854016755,-1.21046366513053));
#608=CARTESIAN_POINT('',(3.70654378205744,0.759831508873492,-1.16471089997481));
#609=CARTESIAN_POINT('',(3.71465054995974,0.715461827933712,-1.14888483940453));
#610=CARTESIAN_POINT('',(3.73084654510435,0.627034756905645,-1.11636399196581));
#611=CARTESIAN_POINT('',(3.73893577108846,0.582977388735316,-1.0996691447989));
#612=CARTESIAN_POINT('',(3.75506834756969,0.494532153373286,-1.06556161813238));
#613=CARTESIAN_POINT('',(3.76311008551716,0.450146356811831,-1.04814286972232));
#614=CARTESIAN_POINT('',(3.77890797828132,0.361339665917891,-1.01330955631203));
#615=CARTESIAN_POINT('',(3.78666422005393,0.316918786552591,-0.995894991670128));
#616=CARTESIAN_POINT('',(3.80170787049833,0.227715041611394,-0.961929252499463));
#617=CARTESIAN_POINT('',(3.80899580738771,0.182932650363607,-0.945377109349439));
#618=CARTESIAN_POINT('',(3.8193814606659,0.115027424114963,-0.922318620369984));
#619=CARTESIAN_POINT('',(3.82275430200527,0.0922554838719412,-0.914923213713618));
#620=CARTESIAN_POINT('',(3.82926378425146,0.0463860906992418,-0.901039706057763));
#621=CARTESIAN_POINT('',(3.83240024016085,0.0232883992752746,-0.894552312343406));
#622=CARTESIAN_POINT('',(3.83538975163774,0.,-0.888681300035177));
#623=B_SPLINE_CURVE_WITH_KNOTS('',3,(#597,#598,#599,#600,#601,#602,#603,#604,#605,#606,#607,
#608,#609,#610,#611,#612,#613,#614,#615,#616,#617,#618,#619,#620,#621,#622),.UNSPECIFIED.,.F.,
.F.,(4,2,2,2,2,2,2,2,2,2,2,2,4),(0.,0.237422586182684,0.474711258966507,0.709891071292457,
0.945019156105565,1.23154825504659,1.37494258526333,1.51834688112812,1.66340969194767,
1.80842794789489,1.95327965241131,2.02579911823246,2.09837476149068),.UNSPECIFIED.);
#624=EDGE_CURVE('E265',#296,#32,#623,.T.);
#625=ORIENTED_EDGE('',*,*,#624,.T.);
#626=ORIENTED_EDGE('',*,*,#33,.F.);
#627=CARTESIAN_POINT('',(-3.83538975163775,0.,-0.888681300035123));
#628=CARTESIAN_POINT('',(-3.83051751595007,0.0378560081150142,-0.898301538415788));
#629=CARTESIAN_POINT('',(-3.82527800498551,0.075207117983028,-0.909424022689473));
#630=CARTESIAN_POINT('',(-3.81425921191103,0.149157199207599,-0.933583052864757));
#631=CARTESIAN_POINT('',(-3.80848067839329,0.185757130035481,-0.946616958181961));
#632=CARTESIAN_POINT('',(-3.79656551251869,0.25855678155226,-0.973537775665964));
#633=CARTESIAN_POINT('',(-3.79042895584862,0.29475658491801,-0.987424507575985));
#634=CARTESIAN_POINT('',(-3.77790312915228,0.367010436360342,-1.01549935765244));
#635=CARTESIAN_POINT('',(-3.7715137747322,0.403064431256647,-1.02968757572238));
#636=CARTESIAN_POINT('',(-3.75195594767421,0.51208173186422,-1.07240529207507));
#637=CARTESIAN_POINT('',(-3.73853910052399,0.585071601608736,-1.10075749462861));
#638=CARTESIAN_POINT('',(-3.71163229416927,0.731908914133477,-1.15508099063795));
#639=CARTESIAN_POINT('',(-3.69814236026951,0.805756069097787,-1.18105305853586));
#640=CARTESIAN_POINT('',(-3.67197525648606,0.952560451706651,-1.22885625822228));
#641=CARTESIAN_POINT('',(-3.6592858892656,1.02548371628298,-1.25078378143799));
#642=CARTESIAN_POINT('',(-3.63477174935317,1.17259949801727,-1.29065637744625));
#643=CARTESIAN_POINT('',(-3.62294731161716,1.24679249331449,-1.30859991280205));
#644=CARTESIAN_POINT('',(-3.60066480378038,1.39593917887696,-1.33983321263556));
#645=CARTESIAN_POINT('',(-3.59019976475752,1.47088667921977,-1.35314735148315));
#646=CARTESIAN_POINT('',(-3.57096365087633,1.62169151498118,-1.37476209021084));
#647=CARTESIAN_POINT('',(-3.56219148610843,1.69754823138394,-1.3830659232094));
#648=CARTESIAN_POINT('',(-3.55253061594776,1.79241931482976,-1.39001772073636));
#649=CARTESIAN_POINT('',(-3.55068490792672,1.81116695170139,-1.39122534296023));
#650=CARTESIAN_POINT('',(-3.54712001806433,1.84870045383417,-1.39330517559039));
#651=CARTESIAN_POINT('',(-3.54540088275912,1.86748633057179,-1.39417726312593));
#652=CARTESIAN_POINT('',(-3.5420890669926,1.90514346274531,-1.39558102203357));
#653=CARTESIAN_POINT('',(-3.5404968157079,1.9240147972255,-1.39611157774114));
#654=CARTESIAN_POINT('',(-3.53744963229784,1.96176786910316,-1.39682098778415));
#655=CARTESIAN_POINT('',(-3.53599464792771,1.98064959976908,-1.39699997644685));
#656=CARTESIAN_POINT('',(-3.53461000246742,1.9995367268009,-1.397));
#657=B_SPLINE_CURVE_WITH_KNOTS('',3,(#627,#628,#629,#630,#631,#632,#633,#634,#635,#636,#637,
#638,#639,#640,#641,#642,#643,#644,#645,#646,#647,#648,#649,#650,#651,#652,#653,#654,#655,#656),
.UNSPECIFIED.,.F.,.F.,(4,2,2,2,2,2,2,2,2,2,2,2,2,2,4),(0.,0.117951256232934,0.235741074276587,
0.353506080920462,0.471310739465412,0.709629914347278,0.947871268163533,1.17937006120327,
1.41095803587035,1.64130751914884,1.8715081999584,1.92813714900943,1.98478681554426,
2.04162060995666,2.09843268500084),.UNSPECIFIED.);
#658=EDGE_CURVE('E273',#30,#241,#657,.T.);
#659=ORIENTED_EDGE('',*,*,#658,.T.);
#660=EDGE_LOOP('',(#594,#595,#596,#625,#626,#659));
#661=FACE_BOUND('',#660,.T.);
#662=ADVANCED_FACE('F235',(#661),#593,.T.);
#663=ORIENTED_EDGE('',*,*,#584,.T.);
#664=ORIENTED_EDGE('',*,*,#145,.T.);
#665=CARTESIAN_POINT('',(-3.53461000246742,1.9995367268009,1.397));
#666=CARTESIAN_POINT('',(-3.54038566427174,1.92056024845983,1.39700086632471));
#667=CARTESIAN_POINT('',(-3.54741439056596,1.84172264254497,1.39387313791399));
#668=CARTESIAN_POINT('',(-3.56360366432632,1.68474687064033,1.38185084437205));
#669=CARTESIAN_POINT('',(-3.57276300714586,1.6066083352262,1.37295953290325));
#670=CARTESIAN_POINT('',(-3.59275731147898,1.45205231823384,1.35000179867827));
#671=CARTESIAN_POINT('',(-3.6035766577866,1.37562571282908,1.33598207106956));
#672=CARTESIAN_POINT('',(-3.62651629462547,1.22400343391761,1.303289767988));
#673=CARTESIAN_POINT('',(-3.63863629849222,1.14880749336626,1.28461821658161));
#674=CARTESIAN_POINT('',(-3.66646560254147,0.983393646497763,1.23869667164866));
#675=CARTESIAN_POINT('',(-3.68238034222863,0.893485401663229,1.21046366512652));
#676=CARTESIAN_POINT('',(-3.70654378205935,0.75983150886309,1.16471089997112));
#677=CARTESIAN_POINT('',(-3.71465054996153,0.715461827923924,1.14888483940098));
#678=CARTESIAN_POINT('',(-3.73084654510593,0.627034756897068,1.11636399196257));
#679=CARTESIAN_POINT('',(-3.73893577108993,0.582977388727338,1.09966914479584));
#680=CARTESIAN_POINT('',(-3.75506834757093,0.494532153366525,1.06556161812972));
#681=CARTESIAN_POINT('',(-3.76311008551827,0.450146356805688,1.04814286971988));
#682=CARTESIAN_POINT('',(-3.77890797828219,0.361339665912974,1.01330955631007));
#683=CARTESIAN_POINT('',(-3.78666422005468,0.316918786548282,0.995894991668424));
#684=CARTESIAN_POINT('',(-3.80170787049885,0.227715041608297,0.961929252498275));
#685=CARTESIAN_POINT('',(-3.80899580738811,0.182932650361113,0.945377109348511));
#686=CARTESIAN_POINT('',(-3.81938146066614,0.115027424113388,0.922318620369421));
#687=CARTESIAN_POINT('',(-3.82275430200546,0.0922554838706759,0.914923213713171));
#688=CARTESIAN_POINT('',(-3.82926378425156,0.0463860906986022,0.901039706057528));
#689=CARTESIAN_POINT('',(-3.8324002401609,0.0232883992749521,0.894552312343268));
#690=CARTESIAN_POINT('',(-3.83538975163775,0.,0.888681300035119));
#691=B_SPLINE_CURVE_WITH_KNOTS('',3,(#665,#666,#667,#668,#669,#670,#671,#672,#673,#674,#675,
#676,#677,#678,#679,#680,#681,#682,#683,#684,#685,#686,#687,#688,#689,#690),.UNSPECIFIED.,.F.,
.F.,(4,2,2,2,2,2,2,2,2,2,2,2,4),(0.,0.237422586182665,0.474711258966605,0.709891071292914,
0.945019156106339,1.23154825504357,1.37494258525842,1.51834688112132,1.66340969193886,
1.80842794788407,1.95327965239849,2.02579911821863,2.09837476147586),.UNSPECIFIED.);
#692=EDGE_CURVE('E285',#125,#62,#691,.T.);
#693=ORIENTED_EDGE('',*,*,#692,.T.);
#694=ORIENTED_EDGE('',*,*,#63,.F.);
#695=CARTESIAN_POINT('',(3.83538975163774,0.,0.88868130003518));
#696=CARTESIAN_POINT('',(3.83051751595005,0.0378560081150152,0.898301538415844));
#697=CARTESIAN_POINT('',(3.8252780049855,0.0752071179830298,0.909424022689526));
#698=CARTESIAN_POINT('',(3.81425921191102,0.149157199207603,0.933583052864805));
#699=CARTESIAN_POINT('',(3.80848067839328,0.185757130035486,0.946616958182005));
#700=CARTESIAN_POINT('',(3.79656551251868,0.258556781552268,0.973537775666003));
#701=CARTESIAN_POINT('',(3.79042895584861,0.294756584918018,0.987424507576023));
#702=CARTESIAN_POINT('',(3.77790312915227,0.367010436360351,1.01549935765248));
#703=CARTESIAN_POINT('',(3.77151377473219,0.403064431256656,1.02968757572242));
#704=CARTESIAN_POINT('',(3.7519559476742,0.51208173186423,1.0724052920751));
#705=CARTESIAN_POINT('',(3.73853910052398,0.585071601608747,1.10075749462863));
#706=CARTESIAN_POINT('',(3.71163229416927,0.731908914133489,1.15508099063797));
#707=CARTESIAN_POINT('',(3.6981423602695,0.8057560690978,1.18105305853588));
#708=CARTESIAN_POINT('',(3.67197525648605,0.952560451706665,1.22885625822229));
#709=CARTESIAN_POINT('',(3.6592858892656,1.02548371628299,1.25078378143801));
#710=CARTESIAN_POINT('',(3.63477174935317,1.17259949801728,1.29065637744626));
#711=CARTESIAN_POINT('',(3.62294731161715,1.24679249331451,1.30859991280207));
#712=CARTESIAN_POINT('',(3.60066480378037,1.39593917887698,1.33983321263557));
#713=CARTESIAN_POINT('',(3.59019976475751,1.47088667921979,1.35314735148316));
#714=CARTESIAN_POINT('',(3.57096365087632,1.6216915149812,1.37476209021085));
#715=CARTESIAN_POINT('',(3.56219148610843,1.69754823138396,1.3830659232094));
#716=CARTESIAN_POINT('',(3.55253061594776,1.79241931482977,1.39001772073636));
#717=CARTESIAN_POINT('',(3.55068490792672,1.8111669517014,1.39122534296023));
#718=CARTESIAN_POINT('',(3.54712001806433,1.84870045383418,1.39330517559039));
#719=CARTESIAN_POINT('',(3.54540088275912,1.86748633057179,1.39417726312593));
#720=CARTESIAN_POINT('',(3.5420890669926,1.90514346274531,1.39558102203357));
#721=CARTESIAN_POINT('',(3.5404968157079,1.92401479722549,1.39611157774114));
#722=CARTESIAN_POINT('',(3.53744963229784,1.96176786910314,1.39682098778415));
#723=CARTESIAN_POINT('',(3.53599464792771,1.98064959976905,1.39699997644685));
#724=CARTESIAN_POINT('',(3.53461000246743,1.99953672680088,1.397));
#725=B_SPLINE_CURVE_WITH_KNOTS('',3,(#695,#696,#697,#698,#699,#700,#701,#702,#703,#704,#705,
#706,#707,#708,#709,#710,#711,#712,#713,#714,#715,#716,#717,#718,#719,#720,#721,#722,#723,#724),
.UNSPECIFIED.,.F.,.F.,(4,2,2,2,2,2,2,2,2,2,2,2,2,2,4),(0.,0.117951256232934,0.235741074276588,
0.353506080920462,0.471310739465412,0.709629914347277,0.947871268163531,1.17937006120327,
1.41095803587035,1.64130751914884,1.8715081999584,1.92813714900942,1.98478681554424,
2.04162060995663,2.0984326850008),.UNSPECIFIED.);
#726=EDGE_CURVE('E194',#58,#182,#725,.T.);
#727=ORIENTED_EDGE('',*,*,#726,.T.);
#728=ORIENTED_EDGE('',*,*,#185,.T.);
#729=EDGE_LOOP('',(#663,#664,#693,#694,#727,#728));
#730=FACE_BOUND('',#729,.T.);
#731=ADVANCED_FACE('F189',(#730),#593,.T.);
#732=CARTESIAN_POINT('',(0.,0.,0.));
#733=DIRECTION('',(0.,-1.,0.));
#734=DIRECTION('',(1.,0.,0.));
#735=AXIS2_PLACEMENT_3D('',#732,#733,#734);
#736=CONICAL_SURFACE('',#735,1.25729999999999,0.959931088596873);
#737=CARTESIAN_POINT('',(0.,0.1822990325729,0.));
#738=DIRECTION('',(0.,1.,0.));
#739=DIRECTION('',(-1.,0.,0.));
#740=AXIS2_PLACEMENT_3D('',#737,#738,#739);
#741=CIRCLE('',#740,0.996949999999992);
#742=CARTESIAN_POINT('',(-0.996949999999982,0.1822990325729,0.));
#743=VERTEX_POINT('',#742);
#744=EDGE_CURVE('E219',#743,#743,#741,.T.);
#745=ORIENTED_EDGE('',*,*,#744,.T.);
#746=EDGE_LOOP('',(#745));
#747=FACE_BOUND('',#746,.T.);
#748=ORIENTED_EDGE('',*,*,#98,.F.);
#749=EDGE_LOOP('',(#748));
#750=FACE_BOUND('',#749,.T.);
#751=ADVANCED_FACE('F576',(#747,#750),#736,.F.);
#752=CARTESIAN_POINT('',(0.,5.4057009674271,0.));
#753=DIRECTION('',(0.,1.,0.));
#754=DIRECTION('',(-1.,0.,0.));
#755=AXIS2_PLACEMENT_3D('',#752,#753,#754);
#756=CONICAL_SURFACE('',#755,0.996949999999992,0.959931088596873);
#757=ORIENTED_EDGE('',*,*,#539,.T.);
#758=EDGE_LOOP('',(#757));
#759=FACE_BOUND('',#758,.T.);
#760=CARTESIAN_POINT('',(0.,5.4057009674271,0.));
#761=DIRECTION('',(0.,1.,0.));
#762=DIRECTION('',(-1.,0.,0.));
#763=AXIS2_PLACEMENT_3D('',#760,#761,#762);
#764=CIRCLE('',#763,0.996949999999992);
#765=CARTESIAN_POINT('',(-0.996949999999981,5.4057009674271,0.));
#766=VERTEX_POINT('',#765);
#767=EDGE_CURVE('E217',#766,#766,#764,.T.);
#768=ORIENTED_EDGE('',*,*,#767,.F.);
#769=EDGE_LOOP('',(#768));
#770=FACE_BOUND('',#769,.T.);
#771=ADVANCED_FACE('F514',(#759,#770),#756,.F.);
#772=CARTESIAN_POINT('',(0.,5.588,0.));
#773=DIRECTION('',(0.,-1.,0.));
#774=DIRECTION('',(0.,0.,-1.));
#775=AXIS2_PLACEMENT_3D('',#772,#773,#774);
#776=CYLINDRICAL_SURFACE('',#775,0.99695);
#777=ORIENTED_EDGE('',*,*,#744,.F.);
#778=EDGE_LOOP('',(#777));
#779=FACE_BOUND('',#778,.T.);
#780=ORIENTED_EDGE('',*,*,#767,.T.);
#781=EDGE_LOOP('',(#780));
#782=FACE_BOUND('',#781,.T.);
#783=ADVANCED_FACE('F240',(#779,#782),#776,.F.);
#784=CARTESIAN_POINT('',(4.44422838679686,5.30794266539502,-0.465666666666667));
#785=DIRECTION('',(0.300705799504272,0.953716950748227,0.));
#786=DIRECTION('',(-0.953716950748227,0.300705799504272,0.));
#787=AXIS2_PLACEMENT_3D('',#784,#785,#786);
#788=CYLINDRICAL_SURFACE('',#787,0.931333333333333);
#789=ORIENTED_EDGE('',*,*,#557,.F.);
#790=ORIENTED_EDGE('',*,*,#508,.F.);
#791=CARTESIAN_POINT('',(4.90026835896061,6.75431667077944,-0.465666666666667));
#792=DIRECTION('',(0.300705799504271,0.953716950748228,0.));
#793=DIRECTION('',(-0.953716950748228,0.300705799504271,0.));
#794=AXIS2_PLACEMENT_3D('',#791,#792,#793);
#795=CIRCLE('',#794,0.931333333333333);
#796=EDGE_CURVE('E380',#285,#475,#795,.T.);
#797=ORIENTED_EDGE('',*,*,#796,.F.);
#798=ORIENTED_EDGE('',*,*,#328,.F.);
#799=EDGE_LOOP('',(#789,#790,#797,#798));
#800=FACE_BOUND('',#799,.T.);
#801=ADVANCED_FACE('F352',(#800),#788,.T.);
#802=CARTESIAN_POINT('',(6.88920679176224,6.12720679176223,-0.465666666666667));
#803=DIRECTION('',(0.,0.,-1.));
#804=DIRECTION('',(-1.,0.,0.));
#805=AXIS2_PLACEMENT_3D('',#802,#803,#804);
#806=TOROIDAL_SURFACE('',#805,2.08545987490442,0.931333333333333);
#807=ORIENTED_EDGE('',*,*,#796,.T.);
#808=ORIENTED_EDGE('',*,*,#476,.F.);
#809=CARTESIAN_POINT('',(6.94374909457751,4.04246027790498,-0.465666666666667));
#810=DIRECTION('',(-0.999657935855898,-0.0261536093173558,0.));
#811=DIRECTION('',(0.0261536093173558,-0.999657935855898,0.));
#812=AXIS2_PLACEMENT_3D('',#809,#810,#811);
#813=CIRCLE('',#812,0.931333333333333);
#814=EDGE_CURVE('E377',#287,#442,#813,.T.);
#815=ORIENTED_EDGE('',*,*,#814,.F.);
#816=ORIENTED_EDGE('',*,*,#288,.F.);
#817=EDGE_LOOP('',(#807,#808,#815,#816));
#818=FACE_BOUND('',#817,.T.);
#819=ADVANCED_FACE('F348',(#818),#806,.T.);
#820=CARTESIAN_POINT('',(7.04951019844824,0.,-0.465666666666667));
#821=DIRECTION('',(0.,0.,-1.));
#822=DIRECTION('',(-1.,0.,0.));
#823=AXIS2_PLACEMENT_3D('',#820,#821,#822);
#824=TOROIDAL_SURFACE('',#823,4.04384353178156,0.931333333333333);
#825=ORIENTED_EDGE('',*,*,#624,.F.);
#826=ORIENTED_EDGE('',*,*,#297,.F.);
#827=ORIENTED_EDGE('',*,*,#814,.T.);
#828=ORIENTED_EDGE('',*,*,#443,.F.);
#829=ORIENTED_EDGE('',*,*,#42,.F.);
#830=EDGE_LOOP('',(#825,#826,#827,#828,#829));
#831=FACE_BOUND('',#830,.T.);
#832=ADVANCED_FACE('F344',(#831),#824,.T.);
#833=CARTESIAN_POINT('',(-4.90026835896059,6.75431667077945,-0.465666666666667));
#834=DIRECTION('',(0.300705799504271,-0.953716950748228,0.));
#835=DIRECTION('',(0.953716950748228,0.300705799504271,0.));
#836=AXIS2_PLACEMENT_3D('',#833,#834,#835);
#837=CYLINDRICAL_SURFACE('',#836,0.931333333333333);
#838=ORIENTED_EDGE('',*,*,#573,.F.);
#839=ORIENTED_EDGE('',*,*,#268,.F.);
#840=CARTESIAN_POINT('',(-4.90026835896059,6.75431667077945,-0.465666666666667));
#841=DIRECTION('',(-0.300705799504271,0.953716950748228,0.));
#842=DIRECTION('',(-0.953716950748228,-0.300705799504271,0.));
#843=AXIS2_PLACEMENT_3D('',#840,#841,#842);
#844=CIRCLE('',#843,0.931333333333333);
#845=EDGE_CURVE('E370',#353,#259,#844,.T.);
#846=ORIENTED_EDGE('',*,*,#845,.F.);
#847=ORIENTED_EDGE('',*,*,#354,.F.);
#848=EDGE_LOOP('',(#838,#839,#846,#847));
#849=FACE_BOUND('',#848,.T.);
#850=ADVANCED_FACE('F299',(#849),#837,.T.);
#851=CARTESIAN_POINT('',(-6.88920679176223,6.12720679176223,-0.465666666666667));
#852=DIRECTION('',(0.,0.,-1.));
#853=DIRECTION('',(-1.,0.,0.));
#854=AXIS2_PLACEMENT_3D('',#851,#852,#853);
#855=TOROIDAL_SURFACE('',#854,2.08545987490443,0.931333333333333);
#856=ORIENTED_EDGE('',*,*,#845,.T.);
#857=ORIENTED_EDGE('',*,*,#260,.F.);
#858=CARTESIAN_POINT('',(-6.9437490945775,4.04246027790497,-0.465666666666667));
#859=DIRECTION('',(0.999657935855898,-0.0261536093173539,0.));
#860=DIRECTION('',(0.0261536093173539,0.999657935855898,0.));
#861=AXIS2_PLACEMENT_3D('',#858,#859,#860);
#862=CIRCLE('',#861,0.931333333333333);
#863=EDGE_CURVE('E378',#385,#250,#862,.T.);
#864=ORIENTED_EDGE('',*,*,#863,.F.);
#865=ORIENTED_EDGE('',*,*,#386,.F.);
#866=EDGE_LOOP('',(#856,#857,#864,#865));
#867=FACE_BOUND('',#866,.T.);
#868=ADVANCED_FACE('F358',(#867),#855,.T.);
#869=CARTESIAN_POINT('',(-7.04951019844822,0.,-0.465666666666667));
#870=DIRECTION('',(0.,0.,-1.));
#871=DIRECTION('',(-1.,0.,0.));
#872=AXIS2_PLACEMENT_3D('',#869,#870,#871);
#873=TOROIDAL_SURFACE('',#872,4.04384353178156,0.931333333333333);
#874=ORIENTED_EDGE('',*,*,#863,.T.);
#875=ORIENTED_EDGE('',*,*,#251,.F.);
#876=ORIENTED_EDGE('',*,*,#658,.F.);
#877=ORIENTED_EDGE('',*,*,#87,.F.);
#878=ORIENTED_EDGE('',*,*,#417,.F.);
#879=EDGE_LOOP('',(#874,#875,#876,#877,#878));
#880=FACE_BOUND('',#879,.T.);
#881=ADVANCED_FACE('F306',(#880),#873,.T.);
#882=CARTESIAN_POINT('',(4.90026835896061,6.75431667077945,0.465666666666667));
#883=DIRECTION('',(-0.300705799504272,-0.953716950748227,0.));
#884=DIRECTION('',(0.953716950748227,-0.300705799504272,0.));
#885=AXIS2_PLACEMENT_3D('',#882,#883,#884);
#886=CYLINDRICAL_SURFACE('',#885,0.931333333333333);
#887=ORIENTED_EDGE('',*,*,#549,.F.);
#888=ORIENTED_EDGE('',*,*,#211,.F.);
#889=CARTESIAN_POINT('',(4.90026835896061,6.75431667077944,0.465666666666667));
#890=DIRECTION('',(0.300705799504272,0.953716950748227,0.));
#891=DIRECTION('',(-0.953716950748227,0.300705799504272,0.));
#892=AXIS2_PLACEMENT_3D('',#889,#890,#891);
#893=CIRCLE('',#892,0.931333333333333);
#894=EDGE_CURVE('E382',#483,#202,#893,.T.);
#895=ORIENTED_EDGE('',*,*,#894,.F.);
#896=ORIENTED_EDGE('',*,*,#522,.F.);
#897=EDGE_LOOP('',(#887,#888,#895,#896));
#898=FACE_BOUND('',#897,.T.);
#899=ADVANCED_FACE('F303',(#898),#886,.T.);
#900=CARTESIAN_POINT('',(6.88920679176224,6.12720679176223,0.465666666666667));
#901=DIRECTION('',(0.,0.,-1.));
#902=DIRECTION('',(-1.,0.,0.));
#903=AXIS2_PLACEMENT_3D('',#900,#901,#902);
#904=TOROIDAL_SURFACE('',#903,2.08545987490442,0.931333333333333);
#905=ORIENTED_EDGE('',*,*,#894,.T.);
#906=ORIENTED_EDGE('',*,*,#203,.F.);
#907=CARTESIAN_POINT('',(6.94374909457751,4.04246027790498,0.465666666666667));
#908=DIRECTION('',(-0.999657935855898,-0.0261536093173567,0.));
#909=DIRECTION('',(0.0261536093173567,-0.999657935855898,0.));
#910=AXIS2_PLACEMENT_3D('',#907,#908,#909);
#911=CIRCLE('',#910,0.931333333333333);
#912=EDGE_CURVE('E386',#450,#193,#911,.T.);
#913=ORIENTED_EDGE('',*,*,#912,.F.);
#914=ORIENTED_EDGE('',*,*,#491,.F.);
#915=EDGE_LOOP('',(#905,#906,#913,#914));
#916=FACE_BOUND('',#915,.T.);
#917=ADVANCED_FACE('F297',(#916),#904,.T.);
#918=CARTESIAN_POINT('',(7.04951019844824,0.,0.465666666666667));
#919=DIRECTION('',(0.,0.,-1.));
#920=DIRECTION('',(-1.,0.,0.));
#921=AXIS2_PLACEMENT_3D('',#918,#919,#920);
#922=TOROIDAL_SURFACE('',#921,4.04384353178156,0.931333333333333);
#923=ORIENTED_EDGE('',*,*,#59,.F.);
#924=ORIENTED_EDGE('',*,*,#458,.F.);
#925=ORIENTED_EDGE('',*,*,#912,.T.);
#926=ORIENTED_EDGE('',*,*,#194,.F.);
#927=ORIENTED_EDGE('',*,*,#726,.F.);
#928=EDGE_LOOP('',(#923,#924,#925,#926,#927));
#929=FACE_BOUND('',#928,.T.);
#930=ADVANCED_FACE('F292',(#929),#922,.T.);
#931=CARTESIAN_POINT('',(-3.65436939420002,2.80282998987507,0.465666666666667));
#932=DIRECTION('',(-0.300705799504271,0.953716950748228,0.));
#933=DIRECTION('',(-0.953716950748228,-0.300705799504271,0.));
#934=AXIS2_PLACEMENT_3D('',#931,#932,#933);
#935=CYLINDRICAL_SURFACE('',#934,0.931333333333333);
#936=ORIENTED_EDGE('',*,*,#581,.F.);
#937=ORIENTED_EDGE('',*,*,#368,.F.);
#938=CARTESIAN_POINT('',(-4.90026835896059,6.75431667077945,0.465666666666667));
#939=DIRECTION('',(-0.300705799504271,0.953716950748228,0.));
#940=DIRECTION('',(-0.953716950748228,-0.300705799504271,0.));
#941=AXIS2_PLACEMENT_3D('',#938,#939,#940);
#942=CIRCLE('',#941,0.931333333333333);
#943=EDGE_CURVE('E51',#114,#361,#942,.T.);
#944=ORIENTED_EDGE('',*,*,#943,.F.);
#945=ORIENTED_EDGE('',*,*,#159,.F.);
#946=EDGE_LOOP('',(#936,#937,#944,#945));
#947=FACE_BOUND('',#946,.T.);
#948=ADVANCED_FACE('F49',(#947),#935,.T.);
#949=CARTESIAN_POINT('',(-6.88920679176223,6.12720679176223,0.465666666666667));
#950=DIRECTION('',(0.,0.,-1.));
#951=DIRECTION('',(-1.,0.,0.));
#952=AXIS2_PLACEMENT_3D('',#949,#950,#951);
#953=TOROIDAL_SURFACE('',#952,2.08545987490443,0.931333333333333);
#954=ORIENTED_EDGE('',*,*,#943,.T.);
#955=ORIENTED_EDGE('',*,*,#401,.F.);
#956=CARTESIAN_POINT('',(-6.9437490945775,4.04246027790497,0.465666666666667));
#957=DIRECTION('',(0.999657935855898,-0.0261536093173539,0.));
#958=DIRECTION('',(0.0261536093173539,0.999657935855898,0.));
#959=AXIS2_PLACEMENT_3D('',#956,#957,#958);
#960=CIRCLE('',#959,0.931333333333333);
#961=EDGE_CURVE('E389',#116,#393,#960,.T.);
#962=ORIENTED_EDGE('',*,*,#961,.F.);
#963=ORIENTED_EDGE('',*,*,#117,.F.);
#964=EDGE_LOOP('',(#954,#955,#962,#963));
#965=FACE_BOUND('',#964,.T.);
#966=ADVANCED_FACE('F311',(#965),#953,.T.);
#967=CARTESIAN_POINT('',(-7.04951019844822,0.,0.465666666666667));
#968=DIRECTION('',(0.,0.,-1.));
#969=DIRECTION('',(-1.,0.,0.));
#970=AXIS2_PLACEMENT_3D('',#967,#968,#969);
#971=TOROIDAL_SURFACE('',#970,4.04384353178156,0.931333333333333);
#972=ORIENTED_EDGE('',*,*,#961,.T.);
#973=ORIENTED_EDGE('',*,*,#425,.F.);
#974=ORIENTED_EDGE('',*,*,#72,.F.);
#975=ORIENTED_EDGE('',*,*,#692,.F.);
#976=ORIENTED_EDGE('',*,*,#126,.F.);
#977=EDGE_LOOP('',(#972,#973,#974,#975,#976));
#978=FACE_BOUND('',#977,.T.);
#979=ADVANCED_FACE('F308',(#978),#971,.T.);
#980=CLOSED_SHELL('',(#102,#163,#217,#278,#332,#372,#405,#429,#462,#495,#526,#588,#662,#731,
#751,#771,#783,#801,#819,#832,#850,#868,#881,#899,#917,#930,#948,#966,#979));
#981=MANIFOLD_SOLID_BREP('B2',#980);
#982=ADVANCED_BREP_SHAPE_REPRESENTATION('',(#18,#981),#14);
#983=SHAPE_DEFINITION_REPRESENTATION(#9,#982);
ENDSEC;
END-ISO-10303-21;
